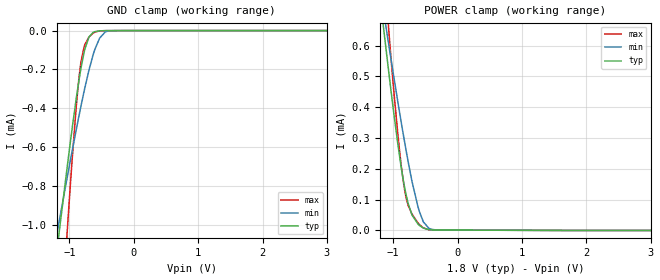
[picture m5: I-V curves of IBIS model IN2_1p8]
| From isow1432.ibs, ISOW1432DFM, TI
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|   IN2_1p8 Model
[Model]   IN2_1p8
Model_type   Input
Vinl = 0.54
Vinh = 1.26
|   typ   min   max
C_comp   0.00095pF   0.00076pF   0.014pF
|  Where Nom  PVT is Nominal Process, 1.8V,  27C
|   Fast PVT is Strong Process,  1.89,  -40C
|   Slow PVT is Weak Process,   1.71V, 150C
[Model spec]
|subparameter
Vinl   0.54   0.513   0.567
Vinh   1.26   1.197   1.323
[Voltage Range]   1.8   1.71   1.89
|Junction Temperature
[Temperature Range]   27   150   -40
[Power Clamp Reference]   1.8   1.71   1.89
[GND Clamp Reference]   0   0   0
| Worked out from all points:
|   GND clamp passes 1 mA (typ) near -1.14 V on its own axis
|   POWER clamp passes 1 mA (typ) near -1.34 V on its own axis
[GND Clamp]
|   Voltage   I(typ)   I(min)   I(max)
-1.8V     -2.874mA   -2.195mA   -5.336mA
-1.184V   -1.11mA    -1.03mA    -1.821mA
-1.163V   -1.051mA   -990.5uA   -1.705mA
-1.028V   -685.9uA   -745.5uA   -1.003mA
-898.2mV  -361uA     -518.7uA   -410.6uA
-828mV    -209.1uA   -401.8uA   -180.8uA
-757.8mV  -93.19uA   -291.9uA   -70.41uA
-698.4mV  -35.37uA   -207.2uA   -34.76uA
-633.6mV  -9.939uA   -127.5uA   -13.49uA
-531mV    -1.3uA     -38.94uA   -1.727uA
-369mV    -252.6nA   -1.435uA   -255.5nA
3.6V      0A         0A         0A
[POWER Clamp]
|   Voltage   I(typ)   I(min)   I(max)
-1.8V     1.872mA    1.618mA    2.869mA
-1.179V   709.9uA    751.6uA    957.8uA
-1.055V   490.2uA    584.4uA    613.4uA
-919.8mV  269.4uA    408.2uA    297.6uA
-871.2mV  199.9uA    347.1uA    205uA
-817.2mV  134.5uA    281.4uA    126.4uA
-768.6mV  89.39uA    225.1uA    82.58uA
-703.8mV  48.86uA    155.9uA    52.03uA
-612mV    20.23uA    74.96uA    23.69uA
-531mV    7.861uA    27.85uA    8.284uA
-293.4mV  1.407uA    1.696uA    1.493uA
3.6V      0A         0A         0A
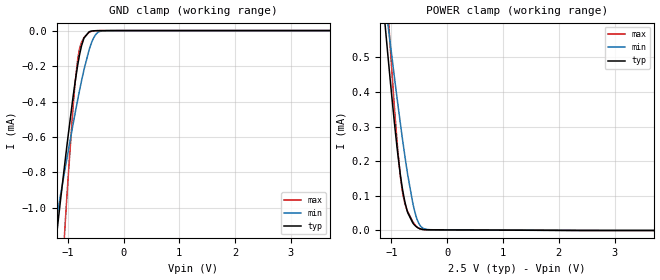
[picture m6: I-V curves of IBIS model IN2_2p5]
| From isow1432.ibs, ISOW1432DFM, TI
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|   IN2_2p5 Model
[Model]   IN2_2p5
Model_type   Input
Vinl = 0.75
Vinh = 1.75
|   typ   min   max
C_comp   0.00095pF   0.00076pF   0.015pF
|  Where Nom  PVT is Nominal Process, 2.5V,   27C
|   Fast PVT is Strong Process,  2.25,   -340C
|   Slow PVT is Weak Process,   2.75V,  150C
[Model spec]
|subparameter
Vinl   0.75   0.675   0.825
Vinh   1.75   1.575   1.925
[Voltage Range]   2.5   2.25   2.75
|Junction Temperature
[Temperature Range]   27   150   -40
[Power Clamp Reference]   2.5   2.25   2.75
[GND Clamp Reference]   0   0   0
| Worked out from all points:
|   GND clamp passes 1 mA (typ) near -1.14 V on its own axis
[GND Clamp]
|   Voltage   I(typ)   I(min)   I(max)
-2.5V     -4.931mA   -3.55mA    -9.461mA
-1.232V   -1.244mA   -1.119mA   -2.084mA
-1.12V    -933.3uA   -912.2uA   -1.477mA
-1.038V   -711.5uA   -762.9uA   -1.052mA
-910mV    -388.8uA   -538.9uA   -458.2uA
-820mV    -193.7uA   -388.8uA   -162.1uA
-782.5mV  -128.6uA   -329.5uA   -96.66uA
-707.5mV  -41.72uA   -219.6uA   -38.86uA
-617.5mV  -7.163uA   -110.2uA   -10.13uA
-497.5mV  -743.2nA   -22.33uA   -887.7nA
-355mV    -237.2nA   -1.074uA   -241.3nA
5V        0A         0A         0A
[POWER Clamp]
|   Voltage   I(typ)   I(min)   I(max)
-2.5V     3.216mA    2.616mA    5.089mA
-1.113V   591.1uA    661.6uA    768.8uA
-1.067V   512.2uA    601.3uA    646.8uA
-1.03V    447.8uA    551.5uA    550.4uA
-902.5mV  243.9uA    386.3uA    263.1uA
-842.5mV  163.5uA    311.9uA    159.8uA
-805mV    122.2uA    267uA      113.4uA
-707.5mV  50.95uA    159.8uA    53.81uA
-602.5mV  18.72uA    68.22uA    21.83uA
-505mV    5.986uA    19.08uA    6.099uA
-302.5mV  1.883uA    2.151uA    2.088uA
5V        0A         0A         0A
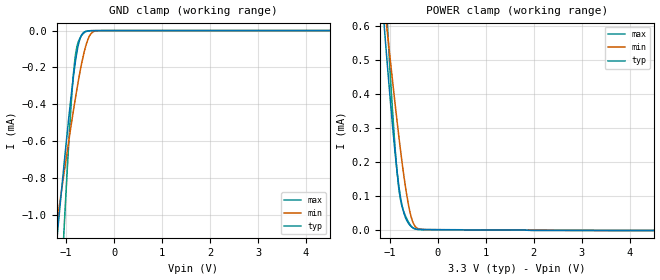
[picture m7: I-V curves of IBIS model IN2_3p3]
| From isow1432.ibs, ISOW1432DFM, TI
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|   IN2_3p3 Model
[Model]   IN2_3p3
Model_type   Input
Vinl = 0.99
Vinh = 2.31
|   typ   min   max
C_comp   0.00096pF   0.00076pF   0.016pF
|  Where Nom  PVT is Nominal Process, 3.3V,   27C
|   Fast PVT is Strong Process,  3.6,   -40C
|   Slow PVT is Weak Process,   3.0V,   150C
[Model spec]
|subparameter
Vinl   0.99   0.9   1.08
Vinh   2.31   2.1   2.52
[Voltage Range]   3.3   3   3.6
|Junction Temperature
[Temperature Range]   27   150   -40
[Power Clamp Reference]   3.3   3   3.6
[GND Clamp Reference]   0   0   0
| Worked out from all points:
|   GND clamp passes 1 mA (typ) near -1.14 V on its own axis
|   POWER clamp passes 1 mA (typ) near -1.34 V on its own axis
[GND Clamp]
|   Voltage   I(typ)   I(min)   I(max)
-3.3V     -7.303mA   -5.115mA   -14.21mA
-1.211V   -1.185mA   -1.08mA    -1.967mA
-1.152V   -1.02mA    -970.1uA   -1.645mA
-1.112V   -911.8uA   -897.7uA   -1.435mA
-1.033V   -699.3uA   -754.7uA   -1.029mA
-904.2mV  -375.1uA   -529uA     -434.5uA
-815.1mV  -184.5uA   -381uA     -151.5uA
-716.1mV  -48.52uA   -231.5uA   -43.07uA
-597.3mV  -4.743uA   -90.13uA   -6.883uA
-498.3mV  -749.9nA   -22.65uA   -899.1nA
-320.1mV  -206.6nA   -565nA     -212.4nA
6.6V      0A         0A         0A
[POWER Clamp]
|   Voltage   I(typ)   I(min)   I(max)
-3.3V     4.765mA    3.768mA    7.646mA
-1.132V   625.6uA    687.8uA    823.2uA
-1.102V   573uA      647.8uA    740.5uA
-1.082V   538.2uA    621.3uA    686.7uA
-1.023V   436uA      542.3uA    533.2uA
-894.3mV  232.2uA    376.1uA    247.6uA
-805.2mV  122.7uA    267.4uA    114uA
-686.4mV  42.1uA     139.1uA    46.68uA
-587.4mV  16.42uA    58.22uA    18.88uA
-498.3mV  6.007uA    17.62uA    6.104uA
-260.7mV  2.368uA    2.521uA    2.632uA
6.6V      0A         0A         0A
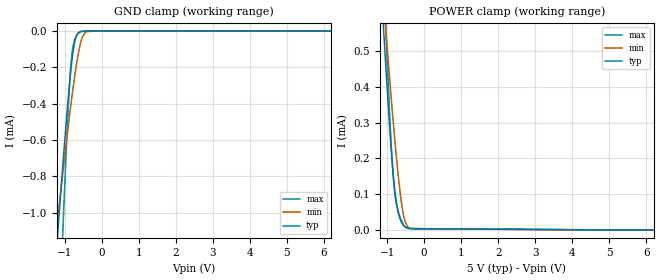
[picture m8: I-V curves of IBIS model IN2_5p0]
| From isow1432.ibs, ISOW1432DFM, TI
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|   IN2_5p0 Model
[Model]   IN2_5p0
Model_type   Input
Vinl = 1.5
Vinh = 3.5
|   typ   min   max
C_comp   0.00096pF   0.00076pF   0.018pF
|  Where Nom  PVT is Nominal Process, 5.0V,   27C
|   Fast PVT is Strong Process,  5.5,   -40C
|   Slow PVT is Weak Process,   4.5V,   150C
[Model spec]
|subparameter
Vinl   1.5   1.35   1.65
Vinh   3.5   3.15   3.85
[Voltage Range]   5   4.5   5.5
|Junction Temperature
[Temperature Range]   27   150   -40
[Power Clamp Reference]   5   4.5   5.5
[GND Clamp Reference]   0   0   0
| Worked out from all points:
|   GND clamp passes 1 mA (typ) near -1.14 V on its own axis
[GND Clamp]
|   Voltage   I(typ)   I(min)   I(max)
-5V       -12.37mA   -8.463mA   -24.37mA
-1.25V    -1.293mA   -1.152mA   -2.181mA
-1.13V    -960.6uA   -930.4uA   -1.53mA
-1.07V    -798uA     -821.4uA   -1.217mA
-1.04V    -718.1uA   -767.4uA   -1.064mA
-905mV    -377uA     -530.3uA   -437.8uA
-815mV    -184.3uA   -380.8uA   -151.3uA
-710mV    -43.61uA   -223uA     -40.05uA
-575mV    -3.015uA   -70.29uA   -4.365uA
-440mV    -371.9nA   -6.928uA   -384.6nA
-200mV    -120.2nA   -149.2nA   -126.1nA
10V       0A         0A         0A
[POWER Clamp]
|   Voltage   I(typ)   I(min)   I(max)
-5V       89.69mA    35.2mA     144.5mA
-1.13V    622.3uA    685.3uA    818.1uA
-1.04V    465uA      564.9uA    576.3uA
-1.025V   439.5uA    545.1uA    538.7uA
-890mV    226.5uA    370.8uA    240.3uA
-845mV    167.3uA    315.2uA    164.6uA
-800mV    118.2uA    261.5uA    109.6uA
-710mV    53.36uA    162.7uA    56.04uA
-605mV    20.56uA    70.71uA    23.91uA
-530mV    9.672uA    28.81uA    10.36uA
-440mV    4.592uA    8.518uA    4.797uA
10V       0A         0A         0A
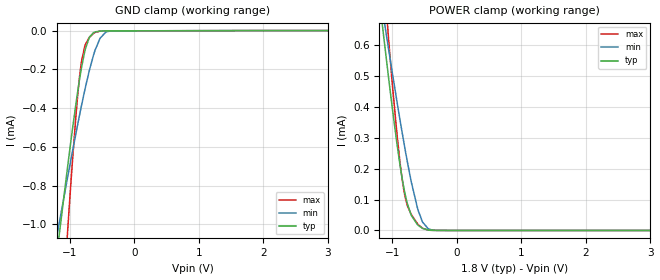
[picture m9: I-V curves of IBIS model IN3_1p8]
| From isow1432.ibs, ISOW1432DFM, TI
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|   IN1_1p8 Model
[Model]   IN3_1p8
Model_type   Input
Vinl = 0.828
Vinh = 1.062
|   typ   min   max
C_comp   0.00095pF   0.00076pF   0.0142pF
|  Where Nom  PVT is Nominal Process, 1.8V,  27C
|   Fast PVT is Strong Process,  1.89,  -40C
|   Slow PVT is Weak Process,   1.71V, 150C
[Model spec]
|subparameter
Vinl   0.828   0.563   1.096
Vinh   1.062   0.718   1.474
[Voltage Range]   1.8   1.71   1.89
|Junction Temperature
[Temperature Range]   27   150   -40
[Power Clamp Reference]   1.8   1.71   1.89
[GND Clamp Reference]   0   0   0
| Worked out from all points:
|   GND clamp passes 1 mA (typ) near -1.14 V on its own axis
|   POWER clamp passes 1 mA (typ) near -1.34 V on its own axis
[GND Clamp]
|   Voltage   I(typ)   I(min)   I(max)
-1.8V     -2.874mA   -2.195mA   -5.336mA
-1.184V   -1.11mA    -1.03mA    -1.821mA
-1.163V   -1.051mA   -990.6uA   -1.705mA
-1.028V   -686uA     -745.6uA   -1.004mA
-898.2mV  -361.3uA   -518.9uA   -411.1uA
-828mV    -209.5uA   -402uA     -181.4uA
-757.8mV  -93.79uA   -292.1uA   -71.12uA
-698.4mV  -36.2uA    -207.5uA   -35.59uA
-633.6mV  -10.97uA   -127.9uA   -14.52uA
-531mV    -2.469uA   -39.62uA   -2.975uA
-369mV    -1.445uA   -2.669uA   -1.543uA
3.6V      0A         0A         0A
[POWER Clamp]
|   Voltage   I(typ)   I(min)   I(max)
-1.8V     1.872mA    1.618mA    2.869mA
-1.179V   709.8uA    751.5uA    957.6uA
-1.055V   490uA      584.3uA    612.9uA
-919.8mV  269uA      408.1uA    296.9uA
-871.2mV  199.5uA    346.9uA    204.2uA
-817.2mV  133.9uA    281.2uA    125.6uA
-768.6mV  88.65uA    224.9uA    81.75uA
-703.8mV  48uA       155.6uA    51.14uA
-612mV    19.26uA    74.45uA    22.69uA
-531mV    6.785uA    27.03uA    7.136uA
-293.4mV  209.8nA    425.9nA    202.8nA
3.6V      0A         0A         0A
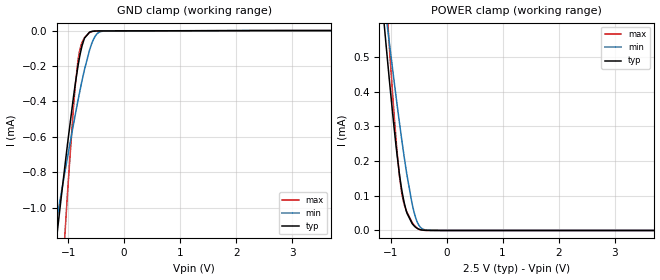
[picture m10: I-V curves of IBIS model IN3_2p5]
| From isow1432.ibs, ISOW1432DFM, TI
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|   IN3_2p5 Model
[Model]   IN3_2p5
Model_type   Input
Vinl = 1.05
Vinh = 1.275
|   typ   min   max
C_comp   0.00095pF   0.00076pF   0.015pF
|  Where Nom  PVT is Nominal Process, 2.5V,   27C
|   Fast PVT is Strong Process,  2.25,   -340C
|   Slow PVT is Weak Process,   2.75V,  150C
[Model spec]
|subparameter
Vinl   1.05   0.697   1.457
Vinh   1.275   0.855   1.815
[Voltage Range]   2.5   2.25   2.75
|Junction Temperature
[Temperature Range]   27   150   -40
[Power Clamp Reference]   2.5   2.25   2.75
[GND Clamp Reference]   0   0   0
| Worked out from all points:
|   GND clamp passes 1 mA (typ) near -1.14 V on its own axis
[GND Clamp]
|   Voltage   I(typ)   I(min)   I(max)
-2.5V     -4.931mA   -3.55mA    -9.461mA
-1.232V   -1.244mA   -1.119mA   -2.084mA
-1.12V    -933.5uA   -912.3uA   -1.477mA
-1.038V   -711.7uA   -763uA     -1.052mA
-910mV    -389.1uA   -539.1uA   -459uA
-820mV    -194.3uA   -389.1uA   -163uA
-782.5mV  -129.3uA   -329.8uA   -97.62uA
-707.5mV  -42.82uA   -219.9uA   -40.05uA
-617.5mV  -8.649uA   -110.7uA   -11.7uA
-497.5mV  -2.387uA   -23.45uA   -2.737uA
-355mV    -1.896uA   -2.716uA   -2.116uA
5V        0A         0A         0A
[POWER Clamp]
|   Voltage   I(typ)   I(min)   I(max)
-2.5V     3.216mA    2.616mA    5.089mA
-1.113V   590.9uA    661.5uA    768.3uA
-1.067V   512uA      601.2uA    646.2uA
-1.03V    447.5uA    551.4uA    549.6uA
-902.5mV  243.4uA    386.1uA    262.1uA
-842.5mV  162.8uA    311.7uA    158.7uA
-805mV    121.3uA    266.8uA    112.2uA
-722.5mV  57.6uA     174.8uA    58.38uA
-617.5mV  20.43uA    78.61uA    24.1uA
-497.5mV  3.903uA    15.71uA    3.749uA
-257.5mV  171.2nA    276.9nA    172.3nA
5V        0A         0A         0A
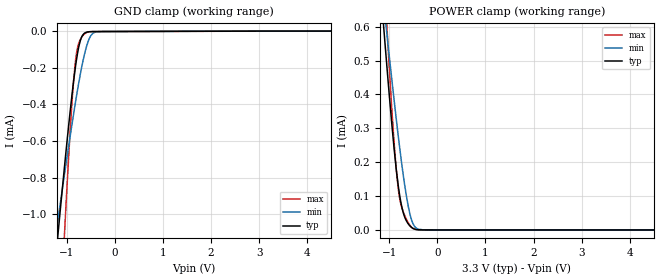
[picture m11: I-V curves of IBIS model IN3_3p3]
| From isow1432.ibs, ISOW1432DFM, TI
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|   IN3_3p3 Model
[Model]   IN3_3p3
Model_type   Input
Vinl = 1.254
Vinh = 1.551
|   typ   min   max
C_comp   0.00096pF   0.00076pF   0.016pF
|  Where Nom  PVT is Nominal Process, 3.3V,   27C
|   Fast PVT is Strong Process,  3.6,   -40C
|   Slow PVT is Weak Process,   3.0V,   150C
[Model spec]
|subparameter
Vinl   1.254   0.87   1.728
Vinh   1.551   1.08   2.088
[Voltage Range]   3.3   3   3.6
|Junction Temperature
[Temperature Range]   27   150   -40
[Power Clamp Reference]   3.3   3   3.6
[GND Clamp Reference]   0   0   0
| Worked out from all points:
|   GND clamp passes 1 mA (typ) near -1.14 V on its own axis
|   POWER clamp passes 1 mA (typ) near -1.34 V on its own axis
[GND Clamp]
|   Voltage   I(typ)   I(min)   I(max)
-3.3V     -7.303mA   -5.115mA   -14.21mA
-1.211V   -1.185mA   -1.08mA    -1.967mA
-1.152V   -1.02mA    -970.3uA   -1.646mA
-1.112V   -912uA     -897.9uA   -1.436mA
-1.033V   -699.6uA   -754.9uA   -1.03mA
-904.2mV  -375.5uA   -529.2uA   -435.5uA
-815.1mV  -185.3uA   -381.3uA   -152.7uA
-716.1mV  -49.91uA   -231.9uA   -44.58uA
-597.3mV  -6.774uA   -90.92uA   -9.051uA
-458.7mV  -2.634uA   -12.21uA   -2.924uA
-260.7mV  -2.357uA   -2.487uA   -2.627uA
6.6V      0A         0A         0A
[POWER Clamp]
|   Voltage   I(typ)   I(min)   I(max)
-3.3V     4.765mA    3.768mA    7.646mA
-1.132V   625.4uA    687.7uA    822.6uA
-1.102V   572.7uA    647.7uA    739.9uA
-1.082V   538uA      621.1uA    686uA
-1.023V   435.6uA    542.1uA    532.2uA
-894.3mV  231.5uA    375.8uA    246.2uA
-805.2mV  121.5uA    267uA      112.4uA
-716.1mV  54.13uA    168.1uA    55.82uA
-617.1mV  20.34uA    78.3uA     23.99uA
-547.8mV  8.703uA    34.54uA    9.499uA
-468.6mV  2.306uA    9.387uA    2.038uA
6.6V      0A         0A         0A
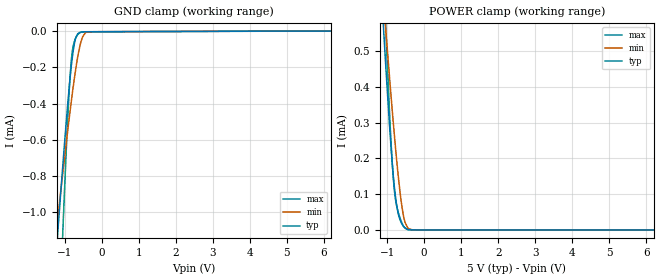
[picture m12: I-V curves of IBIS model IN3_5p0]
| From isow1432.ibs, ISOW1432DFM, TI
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|   IN3_5p0 Model
[Model]   IN3_5p0
Model_type   Input
Vinl = 1.765
Vinh = 2.24
|   typ   min   max
C_comp   0.00096pF   0.00076pF   0.018pF
|  Where Nom  PVT is Nominal Process, 5.0V,   27C
|   Fast PVT is Strong Process,  5.5,   -40C
|   Slow PVT is Weak Process,   4.5V,   150C
[Model spec]
|subparameter
Vinl   1.765   1.215   2.365
Vinh   2.24   1.575   2.981
[Voltage Range]   5   4.5   5.5
|Junction Temperature
[Temperature Range]   27   150   -40
[Power Clamp Reference]   5   4.5   5.5
[GND Clamp Reference]   0   0   0
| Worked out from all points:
|   GND clamp passes 1 mA (typ) near -1.14 V on its own axis
[GND Clamp]
|   Voltage   I(typ)   I(min)   I(max)
-5V       -12.37mA   -8.463mA   -24.37mA
-1.25V    -1.294mA   -1.152mA   -2.181mA
-1.13V    -960.9uA   -930.7uA   -1.531mA
-1.07V    -798.4uA   -821.7uA   -1.218mA
-1.04V    -718.5uA   -767.7uA   -1.066mA
-905mV    -377.6uA   -530.7uA   -439.3uA
-815mV    -185.5uA   -381.3uA   -153.1uA
-710mV    -45.79uA   -223.7uA   -42.4uA
-575mV    -6.18uA    -71.65uA   -7.828uA
-440mV    -3.687uA   -9.849uA   -4.127uA
-230mV    -3.463uA   -3.541uA   -3.899uA
10V       0A         0A         0A
[POWER Clamp]
|   Voltage   I(typ)   I(min)   I(max)
-5V       89.69mA    35.2mA     144.5mA
-1.13V    622uA      685.1uA    817.3uA
-1.04V    464.6uA    564.6uA    574.9uA
-1.025V   439uA      544.8uA    537.1uA
-890mV    225.4uA    370.4uA    238.1uA
-845mV    165.8uA    314.7uA    162.3uA
-800mV    116.3uA    260.9uA    107.2uA
-710mV    51uA       161.9uA    53.46uA
-605mV    17.84uA    69.31uA    20.95uA
-530mV    6.674uA    26.62uA    7.004uA
-440mV    1.342uA    5.478uA    1.111uA
10V       0A         0A         0A
